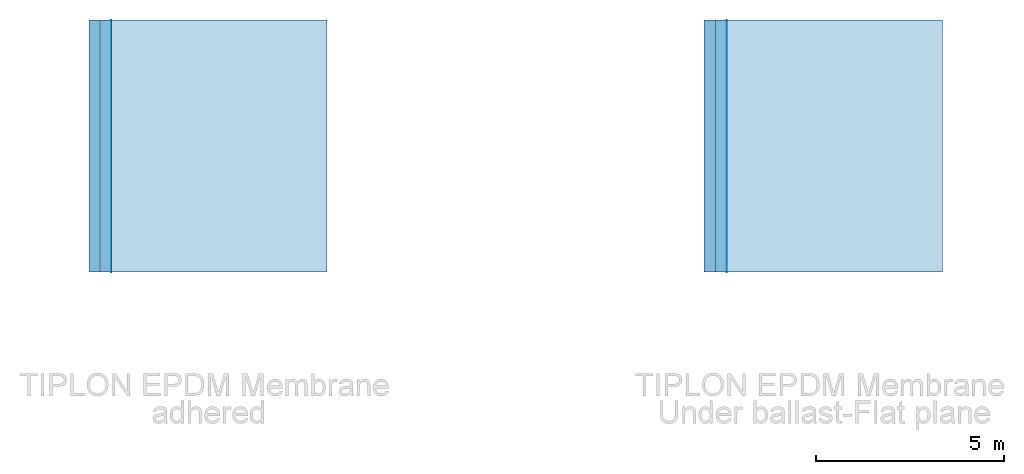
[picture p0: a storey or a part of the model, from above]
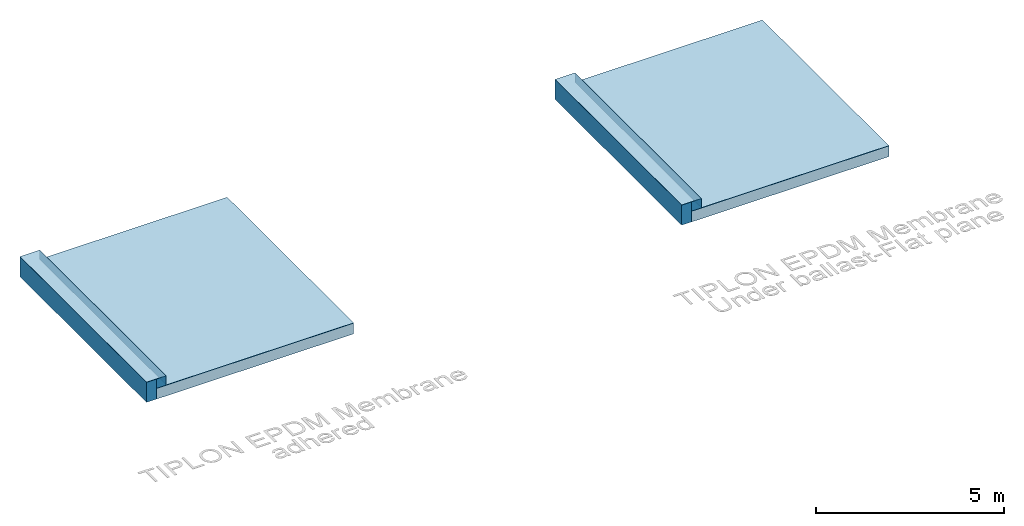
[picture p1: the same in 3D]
Properties of the parts of a building model (IFC2X3)

# File
Description: ViewDefinition [CoordinationView_V2.0], RevitIdentifiers [ContentGUID: ba8bcfdc-dbaa-49fa-ac56-a6aa088a99af, VersionGUID: 73794f59-2237-48ac-86da-4e38d79fa2c1, NumberOfSaves: 85], CoordinateReference [CoordinateBase: Coordonnées partagées]
File name: GENERIC_Roof_VMBSO_TIPLON_EPDM_Rvt2025.ifc
Time: 2026-01-30T12:01:32+01:00
Written by: ODA SDAI 24.12
Made in: Autodesk Revit 25.3.0.46 (FRA) - IFC 25.3.0.46

# IfcSite, Default
RefLatitude: 42, 24, 53, 508911; RefLongitude: -71, -15, -29, -58837; RefElevation: 0 mm

# IfcBuilding
Pset_BuildingCommon - NumberOfStoreys: 1

# IfcBuildingStorey: Niveau:Niveau 1, Niveau 1
LongName: Niveau 1; Elevation: 0 mm

# IfcBuildingElementProxy: Texte 3D:Model Text 1 (2)
In: Niveau 1
Pset_BuildingElementProxyCommon - Reference: Model Text 1; sets with these values: 2
Name (Texte 3D:Model Text 1:...)
24701
24706

# IfcRoof: Toit de base:Tiplon Membrane EPDM adhered-Flat plane, Toit de base:Tiplon Membrane EPDM adhered-Flat plane:25614
In: Niveau 1
Material: Tiplon Membrane EPDM adhered_Flat plane 1.5 mm, Contact adhesive Tiplon 1.1 mm
Pset_QuantityTakeOff - Reference: Tiplon Membrane EPDM adhered-Flat plane
Pset_RoofCommon - Reference: Tiplon Membrane EPDM adhered-Flat plane; IsExternal: yes; ProjectedArea: 38.5877 m2; TotalArea: 38.5877 m2

# IfcRoof: Toit de base:Tiplon Membrane EPDM adhered_Upstands (2)
In: Niveau 1
Material: Tiplon Membrane EPDM adhered_Upstand 1.5 mm, Contact adhesive Tiplon 1.1 mm
Pset_ManufacturerTypeInformation - Manufacturer: VM BUILDING SOLUTIONS
Pset_QuantityTakeOff - Reference: Tiplon Membrane EPDM adhered_Upstands
Pset_RoofCommon - IsExternal: yes; Reference: Tiplon Membrane EPDM adhered_Upstands; ProjectedArea: 4.05083 m2; TotalArea: 4.05083 m2
Name (Toit de base:Tiplon Membrane EPDM adhered_Upstands:...)
31611
32271

# IfcRoof: Toit de base:Tiplon Membrane EPDM under ballast-Flat plane, Toit de base:Tiplon Membrane EPDM under ballast-Flat plane:26349
In: Niveau 1
Material: Polyester protective film 0.8 mm, Tiplon Membrane EPDM under ballast_Flat plane 1.5 mm
Pset_QuantityTakeOff - Reference: Tiplon Membrane EPDM under ballast-Flat plane
Pset_RoofCommon - IsExternal: yes; Reference: Tiplon Membrane EPDM under ballast-Flat plane; ProjectedArea: 38.5877 m2; TotalArea: 38.5877 m2

# IfcRoof: Toit de base:Toit-Support autorisé (2)
In: Niveau 1
Material: Isolation 100 mm, Pare vapeur 0.8 mm, Béton de pente 50 mm, Structure porteuse 200 mm
Pset_QuantityTakeOff - Reference: Toit-Support autorisé
Pset_RoofCommon - IsExternal: yes; Reference: Toit-Support autorisé; ProjectedArea: 40.602 m2; TotalArea: 40.602 m2
Name (Toit de base:Toit-Support autorisé:...)
31936
32010

# IfcSlab: Toit de base:Tiplon Membrane EPDM adhered-Flat plane, Toit de base:Tiplon Membrane EPDM adhered-Flat plane:25614
In: Niveau 1
PredefinedType: ROOF; Material: Tiplon Membrane EPDM adhered_Flat plane 1.5 mm, Contact adhesive Tiplon 1.1 mm
Pset_QuantityTakeOff - Reference: Tiplon Membrane EPDM adhered-Flat plane; sets with these values: 2
Pset_SlabCommon - Reference: Tiplon Membrane EPDM adhered-Flat plane; IsExternal: yes; PitchAngle: 0 deg

# IfcSlab: Toit de base:Tiplon Membrane EPDM adhered_Upstands (2)
In: Niveau 1
PredefinedType: ROOF; Material: Tiplon Membrane EPDM adhered_Upstand 1.5 mm, Contact adhesive Tiplon 1.1 mm
Pset_QuantityTakeOff - Reference: Tiplon Membrane EPDM adhered_Upstands; sets with these values: 2
Pset_SlabCommon - IsExternal: yes; PitchAngle: 0 deg; Reference: Tiplon Membrane EPDM adhered_Upstands
Name (Toit de base:Tiplon Membrane EPDM adhered_Upstands:...)
31611
32271

# IfcSlab: Toit de base:Tiplon Membrane EPDM under ballast-Flat plane, Toit de base:Tiplon Membrane EPDM under ballast-Flat plane:26349
In: Niveau 1
PredefinedType: ROOF; Material: Polyester protective film 0.8 mm, Tiplon Membrane EPDM under ballast_Flat plane 1.5 mm
Pset_QuantityTakeOff - Reference: Tiplon Membrane EPDM under ballast-Flat plane; sets with these values: 2
Pset_SlabCommon - IsExternal: yes; PitchAngle: 0 deg; Reference: Tiplon Membrane EPDM under ballast-Flat plane

# IfcSlab: Toit de base:Toit-Support autorisé (2)
In: Niveau 1
PredefinedType: ROOF; Material: Isolation 100 mm, Pare vapeur 0.8 mm, Béton de pente 50 mm, Structure porteuse 200 mm
Pset_QuantityTakeOff - Reference: Toit-Support autorisé; sets with these values: 2
Pset_SlabCommon - IsExternal: yes; PitchAngle: 0 deg; Reference: Toit-Support autorisé
Name (Toit de base:Toit-Support autorisé:...)
31936
32010

# IfcWallStandardCase: Mur de base:Mur 1 (4)
In: Niveau 1
Type - PredefinedType: STANDARD; Material: Isolation 100 mm, Maçonnerie ascendante 200 mm
Pset_QuantityTakeOff - Reference: Mur 1; sets with these values: 2
Pset_WallCommon - IsExternal: yes; Reference: Mur 1; ExtendToStructure: no; LoadBearing: no
Name (Mur de base:Mur 1:...)
25626
25627
26361
26362

# IfcWallStandardCase: Mur de base:Tiplon Membrane EPDM adhered-Upstand (2)
In: Niveau 1
Type - PredefinedType: STANDARD; Material: Tiplon Membrane EPDM adhered_Upstand 1.5 mm, Contact adhesive Tiplon 1.1 mm
Type - Pset_ReinforcementBarPitchOfWall - Description: Membrane with internal reinforcement. Available with pre-tape. Top range.
Pset_QuantityTakeOff - Reference: Tiplon Membrane EPDM adhered-Upstand; sets with these values: 2
Pset_WallCommon - IsExternal: yes; ExtendToStructure: no; LoadBearing: no; Reference: Tiplon Membrane EPDM adhered-Upstand
Name (Mur de base:Tiplon Membrane EPDM adhered-Upstand:...)
25628
26363
